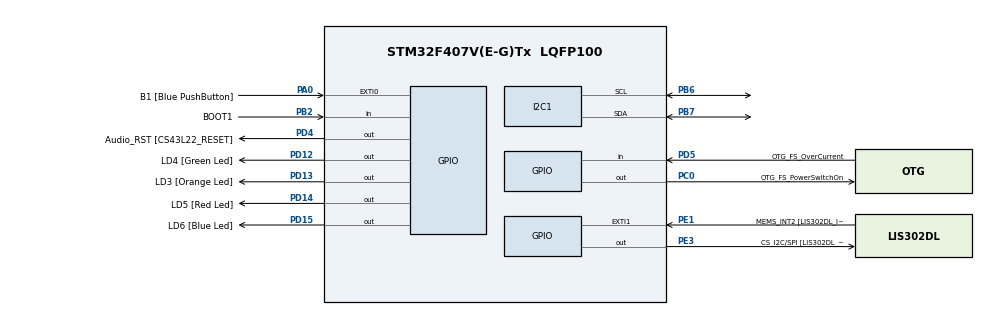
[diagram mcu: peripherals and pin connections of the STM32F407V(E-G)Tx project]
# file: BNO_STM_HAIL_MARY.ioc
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Mcu.Family=STM32F4
Mcu.Name=STM32F407V(E-G)Tx
Mcu.Package=LQFP100
NVIC.PriorityGroup=NVIC_PRIORITYGROUP_0
PA0-WKUP.GPIO_Label=B1 [Blue PushButton]
PA0-WKUP.Signal=GPXTI0
PA10.GPIO_Label=OTG_FS_ID
PA10.GPIO_Mode=GPIO_MODE_AF_PP
PA10.GPIO_PuPd=GPIO_NOPULL
PA10.GPIO_Speed=GPIO_SPEED_FREQ_LOW
PA10.Signal=USB_OTG_FS_ID
PA11.GPIO_Label=OTG_FS_DM
PA11.GPIO_Mode=GPIO_MODE_AF_PP
PA11.GPIO_PuPd=GPIO_NOPULL
PA11.GPIO_Speed=GPIO_SPEED_FREQ_LOW
PA11.Signal=USB_OTG_FS_DM
PA12.GPIO_Label=OTG_FS_DP
PA12.GPIO_Mode=GPIO_MODE_AF_PP
PA12.GPIO_PuPd=GPIO_NOPULL
PA12.GPIO_Speed=GPIO_SPEED_FREQ_LOW
PA12.Signal=USB_OTG_FS_DP
PA13.GPIO_Label=SWDIO
PA13.Signal=SYS_JTMS-SWDIO
PA14.GPIO_Label=SWCLK
PA14.Signal=SYS_JTCK-SWCLK
PA4.GPIO_Label=I2S3_WS [CS43L22_LRCK]
PA4.GPIO_Mode=GPIO_MODE_AF_PP
PA4.GPIO_PuPd=GPIO_NOPULL
PA4.GPIO_Speed=GPIO_SPEED_FREQ_LOW
PA4.Signal=I2S3_WS
PA5.GPIO_Label=SPI1_SCK [LIS302DL_SCL/SPC]
PA5.GPIO_Mode=GPIO_MODE_AF_PP
PA5.GPIO_PuPd=GPIO_NOPULL
PA5.GPIO_Speed=GPIO_SPEED_FREQ_LOW
PA5.Signal=SPI1_SCK
PA6.GPIO_Label=SPI1_MISO [LIS302DL_SDO]
PA6.GPIO_Mode=GPIO_MODE_AF_PP
PA6.GPIO_PuPd=GPIO_NOPULL
PA6.GPIO_Speed=GPIO_SPEED_FREQ_LOW
PA6.Signal=SPI1_MISO
PA7.GPIO_Label=SPI1_MOSI [LIS302DL_SDA/SDI/SDO]
PA7.GPIO_Mode=GPIO_MODE_AF_PP
PA7.GPIO_PuPd=GPIO_NOPULL
PA7.GPIO_Speed=GPIO_SPEED_FREQ_LOW
PA7.Signal=SPI1_MOSI
PA9.GPIO_Label=VBUS_FS
PA9.GPIO_Mode=GPIO_MODE_INPUT
PA9.GPIO_PuPd=GPIO_NOPULL
PA9.Signal=USB_OTG_FS_VBUS
PB10.GPIO_Label=CLK_IN [MP45DT02_CLK]
PB10.GPIO_Mode=GPIO_MODE_AF_PP
PB10.GPIO_PuPd=GPIO_NOPULL
PB10.GPIO_Speed=GPIO_SPEED_FREQ_LOW
PB10.Signal=I2S2_CK
PB2.GPIO_Label=BOOT1
PB2.GPIO_Mode=GPIO_MODE_INPUT
PB2.GPIO_PuPd=GPIO_NOPULL
PB2.Signal=GPIO_Input
PB3.GPIO_Label=SWO
PB3.Signal=SYS_JTDO-SWO
PB6.Mode=I2C
PB6.Signal=I2C1_SCL
PB7.Mode=I2C
PB7.Signal=I2C1_SDA
PC0.GPIO_Label=OTG_FS_PowerSwitchOn
PC0.GPIO_PuPd=GPIO_NOPULL
PC0.GPIO_Speed=GPIO_SPEED_FREQ_LOW
PC0.PinState=GPIO_PIN_SET
PC0.Signal=GPIO_Output
PC10.GPIO_Label=I2S3_SCK [CS43L22_SCLK]
PC10.GPIO_Mode=GPIO_MODE_AF_PP
PC10.GPIO_PuPd=GPIO_NOPULL
PC10.GPIO_Speed=GPIO_SPEED_FREQ_LOW
PC10.Signal=I2S3_CK
PC12.GPIO_Label=I2S3_SD [CS43L22_SDIN]
PC12.GPIO_Mode=GPIO_MODE_AF_PP
PC12.GPIO_PuPd=GPIO_NOPULL
PC12.GPIO_Speed=GPIO_SPEED_FREQ_LOW
PC12.Signal=I2S3_SD
PC14-OSC32_IN.GPIO_Label=PC14-OSC32_IN
PC14-OSC32_IN.Signal=RCC_OSC32_IN
PC15-OSC32_OUT.GPIO_Label=PC15-OSC32_OUT
PC15-OSC32_OUT.Signal=RCC_OSC32_OUT
PC3.GPIO_Label=PDM_OUT [MP45DT02_DOUT]
PC3.GPIO_Mode=GPIO_MODE_AF_PP
PC3.GPIO_PuPd=GPIO_NOPULL
PC3.GPIO_Speed=GPIO_SPEED_FREQ_LOW
PC3.Signal=I2S2_SD
PC7.GPIO_Label=I2S3_MCK [CS43L22_MCLK]
PC7.GPIO_Mode=GPIO_MODE_AF_PP
PC7.GPIO_PuPd=GPIO_NOPULL
PC7.GPIO_Speed=GPIO_SPEED_FREQ_LOW
PC7.Signal=I2S3_MCK
PD12.GPIO_Label=LD4 [Green Led]
PD12.GPIO_PuPd=GPIO_NOPULL
PD12.GPIO_Speed=GPIO_SPEED_FREQ_LOW
PD12.Signal=GPIO_Output
PD13.GPIO_Label=LD3 [Orange Led]
PD13.GPIO_PuPd=GPIO_NOPULL
PD13.GPIO_Speed=GPIO_SPEED_FREQ_LOW
PD13.Signal=GPIO_Output
PD14.GPIO_Label=LD5 [Red Led]
PD14.GPIO_PuPd=GPIO_NOPULL
PD14.GPIO_Speed=GPIO_SPEED_FREQ_LOW
PD14.Signal=GPIO_Output
PD15.GPIO_Label=LD6 [Blue Led]
PD15.GPIO_PuPd=GPIO_NOPULL
PD15.GPIO_Speed=GPIO_SPEED_FREQ_LOW
PD15.Signal=GPIO_Output
PD4.GPIO_Label=Audio_RST [CS43L22_RESET]
PD4.GPIO_PuPd=GPIO_NOPULL
PD4.GPIO_Speed=GPIO_SPEED_FREQ_LOW
PD4.Signal=GPIO_Output
PD5.GPIO_Label=OTG_FS_OverCurrent
PD5.GPIO_Mode=GPIO_MODE_INPUT
PD5.GPIO_PuPd=GPIO_NOPULL
PD5.Signal=GPIO_Input
PE1.GPIO_Label=MEMS_INT2 [LIS302DL_INT2]
PE1.GPIO_ModeDefaultEXTI=GPIO_MODE_EVT_RISING
PE1.GPIO_PuPd=GPIO_NOPULL
PE1.Signal=GPXTI1
PE3.GPIO_Label=CS_I2C/SPI [LIS302DL_CS_I2C/SPI]
PE3.GPIO_PuPd=GPIO_NOPULL
PE3.GPIO_Speed=GPIO_SPEED_FREQ_LOW
PE3.Signal=GPIO_Output
PH0-OSC_IN.GPIO_Label=PH0-OSC_IN
PH0-OSC_IN.Signal=RCC_OSC_IN
PH1-OSC_OUT.GPIO_Label=PH1-OSC_OUT
PH1-OSC_OUT.Signal=RCC_OSC_OUT
ProjectManager.HeapSize=0x200
ProjectManager.StackSize=0x400
ProjectManager.TargetToolchain=STM32CubeIDE
RCC.48MHZClocksFreq_Value=24000000
RCC.AHBCLKDivider=RCC_SYSCLK_DIV2
RCC.AHBFreq_Value=42000000
RCC.APB1CLKDivider=RCC_HCLK_DIV4
RCC.APB1Freq_Value=10500000
RCC.APB1TimFreq_Value=21000000
RCC.APB2CLKDivider=RCC_HCLK_DIV2
RCC.APB2Freq_Value=21000000
RCC.APB2TimFreq_Value=42000000
RCC.CortexFreq_Value=42000000
RCC.HCLKFreq_Value=42000000
RCC.HSE_VALUE=8000000
RCC.HSI_VALUE=16000000
RCC.LSE_VALUE=32768
RCC.PLLM=8
RCC.PLLN=84
RCC.PLLQ=7
RCC.SYSCLKFreq_VALUE=84000000
RCC.SYSCLKSource=RCC_SYSCLKSOURCE_PLLCLK
RCC.VCOOutputFreq_Value=168000000
board=STM32F407G-DISC1

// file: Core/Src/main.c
#include <stdbool.h>
#include <stdio.h>

//#include "../../../bno055.h"
//#include "../../../bno_config.h"
 #include "bno055.h"
 #include "bno_config.h"
#include "main.h"
//#include "retarget.h"
#include "stm32f4xx_hal.h"
#include "stm32f4xx_hal_gpio.h"
#include "stm32f4xx_hal_gpio_ex.h"

I2C_HandleTypeDef hi2c1;
I2C_HandleTypeDef hi2c2;
bno055_t bno;
error_bno err;

void SystemClock_Config(void);
static void MX_GPIO_Init(void);
static void MX_I2C1_Init(void);

// static void MX_I2C2_Init(void);

int main(void) {
    /* Reset of all peripherals, Initializes the Flash interface and the
     * Systick. */
    HAL_Init();

    /* Configure the system clock */
    SystemClock_Config();
    /* Initialize all configured peripherals */
    MX_GPIO_Init();
//    uart_init();
    MX_I2C1_Init();
    // MX_I2C2_Init();

    bno = (bno055_t){
        .i2c = &hi2c1, .addr = BNO_ADDR, .mode = BNO_MODE_IMU, ._temp_unit = 0,
        // .ptr = &bno,
    };
    HAL_Delay(1000);

    if ((err = bno055_init(&bno)) == BNO_OK) {
        printf("[+] BNO055 init success\r\n");

        HAL_Delay(100);
    } else {
        printf("[!] BNO055 init failed\r\n");
        printf("%s\n", bno055_err_str(err));
        Error_Handler();
    }
    HAL_Delay(100);
    err = bno055_set_unit(&bno, BNO_TEMP_UNIT_C, BNO_GYR_UNIT_DPS,
                          BNO_ACC_UNITSEL_M_S2, BNO_EUL_UNIT_DEG);
    if (err != BNO_OK) {
        printf("[BNO] Failed to set units. Err: %d\r\n", err);
    } else {
        printf("[BNO] Unit selection success\r\n");
    }

    HAL_Delay(1000);
    s8 temperature = 0;
    // f32 acc_x = 0.0f, acc_y = 0.0f, acc_z = 0.0f;
    bno055_vec3_t acc = {0, 0, 0};
    bno055_vec3_t lia = {0, 0, 0};
    bno055_vec3_t gyr = {0, 0, 0};
    bno055_vec3_t mag = {0, 0, 0};
    bno055_vec3_t grv = {0, 0, 0};
    bno055_euler_t eul = {0, 0, 0};
    bno055_vec4_t qua = {0, 0, 0};
    while (1) {
        // bno055_temperature(&bno, &temperature);
        bno.temperature(&bno, &temperature);
        bno.acc(&bno, &acc);
        bno.linear_acc(&bno, &lia);
        bno.gyro(&bno, &gyr);
        bno.mag(&bno, &mag);
        bno.gravity(&bno, &grv);
        bno.euler(&bno, &eul);
        bno.quaternion(&bno, &qua);
        printf("[+] Temperature: %2d°C\r\n", temperature);
//        printf("[+] ACC - x: %+2.2f | y: %+2.2f | z: %+2.2f\r\n", acc.x, acc.y,
//               acc.z);
//        printf("[+] LIA - x: %+2.2f | y: %+2.2f | z: %+2.2f\r\n", lia.x, lia.y,
//               lia.z);
//        printf("[+] GYR - x: %+2.2f | y: %+2.2f | z: %+2.2f\r\n", gyr.x, gyr.y,
//               gyr.z);
//        printf("[+] MAG - x: %+2.2f | y: %+2.2f | z: %+2.2f\r\n", mag.x, mag.y,
//               mag.z);
//        printf("[+] GRV - x: %+2.2f | y: %+2.2f | z: %+2.2f\r\n", grv.x, grv.y,
//               grv.z);
//        printf("[+] Roll: %+2.2f | Pitch: %+2.2f | Yaw: %+2.2f\r\n", eul.roll,
//               eul.pitch, eul.yaw);
//        printf("[+] QUA - w: %+2.2f | x: %+2.2f | y: %+2.2f | z: %+2.2f\r\n",
//               qua.w, qua.x, qua.y, qua.z);
//        HAL_GPIO_TogglePin(STATUS_LED_PORT, STATUS_LED);
        HAL_Delay(100);
    }
}

static void MX_I2C1_Init(void) {
    __HAL_RCC_I2C1_CLK_ENABLE();
    hi2c1.Instance = I2C1;
    hi2c1.Init.ClockSpeed = 100000;
    hi2c1.Init.DutyCycle = I2C_DUTYCYCLE_2;
    hi2c1.Init.OwnAddress1 = 0;
    hi2c1.Init.AddressingMode = I2C_ADDRESSINGMODE_7BIT;
    hi2c1.Init.DualAddressMode = I2C_DUALADDRESS_DISABLE;
    hi2c1.Init.OwnAddress2 = 0;
    hi2c1.Init.GeneralCallMode = I2C_GENERALCALL_DISABLE;
    hi2c1.Init.NoStretchMode = I2C_NOSTRETCH_DISABLE;
    if (HAL_I2C_Init(&hi2c1) != HAL_OK) {
        Error_Handler();
    }
}

// static void MX_I2C2_Init(void) {
//     __HAL_RCC_I2C2_CLK_ENABLE();
//     hi2c2.Instance = I2C2;
//     hi2c2.Init.ClockSpeed = 100000;
//     hi2c2.Init.DutyCycle = I2C_DUTYCYCLE_2;
//     hi2c2.Init.OwnAddress1 = 0;
//     hi2c2.Init.AddressingMode = I2C_ADDRESSINGMODE_7BIT;
//     hi2c2.Init.DualAddressMode = I2C_DUALADDRESS_DISABLE;
//     hi2c2.Init.OwnAddress2 = 0;
//     hi2c2.Init.GeneralCallMode = I2C_GENERALCALL_DISABLE;
//     hi2c2.Init.NoStretchMode = I2C_NOSTRETCH_DISABLE;
//     if (HAL_I2C_Init(&hi2c2) != HAL_OK) {
//         Error_Handler();
//     }
// }

static void MX_GPIO_Init(void) {
    /* GPIO Ports Clock Enable */
    __HAL_RCC_GPIOC_CLK_ENABLE();
    __HAL_RCC_GPIOH_CLK_ENABLE();
    __HAL_RCC_GPIOB_CLK_ENABLE();
    __HAL_RCC_GPIOA_CLK_ENABLE();

    GPIO_InitTypeDef gpio = {0};
    gpio.Speed = GPIO_SPEED_FREQ_LOW;
    gpio.Mode = GPIO_MODE_OUTPUT_PP;
    gpio.Pin = ERROR_LED;
    gpio.Pull = GPIO_NOPULL;
    HAL_GPIO_Init(ERROR_LED_PORT, &gpio);

    gpio.Speed = GPIO_SPEED_FREQ_LOW;
    gpio.Mode = GPIO_MODE_OUTPUT_PP;
    gpio.Pin = STATUS_LED;
    gpio.Pull = GPIO_NOPULL;
    HAL_GPIO_Init(STATUS_LED_PORT, &gpio);

    gpio.Speed = GPIO_SPEED_FREQ_MEDIUM;
    gpio.Mode = GPIO_MODE_AF_OD;
    gpio.Alternate = GPIO_AF4_I2C1;
    gpio.Pin = I2C1_SCL | I2C1_SDA;
    gpio.Pull = GPIO_NOPULL;
    HAL_GPIO_Init(I2C1_PORT, &gpio);

    // gpio.Speed = GPIO_SPEED_FREQ_MEDIUM;
    // gpio.Mode = GPIO_MODE_AF_OD;
    // gpio.Alternate = GPIO_AF4_I2C2;
    // gpio.Pin =  I2C2_SCL;
    // gpio.Pull = GPIO_NOPULL;
    // HAL_GPIO_Init(I2C2_PORT, &gpio);

    // gpio.Speed = GPIO_SPEED_FREQ_MEDIUM;
    // gpio.Mode = GPIO_MODE_AF_OD;
    // gpio.Alternate = GPIO_AF9_I2C2;
    // gpio.Pin =  I2C2_SDA;
    // gpio.Pull = GPIO_NOPULL;
    // HAL_GPIO_Init(I2C2_PORT, &gpio);
}

void SystemClock_Config(void) {
    /* SysTick_IRQn interrupt configuration */
    RCC_OscInitTypeDef RCC_OscInitStruct = {0};
    RCC_ClkInitTypeDef RCC_ClkInitStruct = {0};

    /** Configure the main internal regulator output voltage
     */
    __HAL_RCC_PWR_CLK_ENABLE();
    __HAL_PWR_VOLTAGESCALING_CONFIG(PWR_REGULATOR_VOLTAGE_SCALE1);
    /** Initializes the RCC Oscillators according to the specified parameters
     * in the RCC_OscInitTypeDef structure.
     */
    RCC_OscInitStruct.OscillatorType = RCC_OSCILLATORTYPE_HSI;
    RCC_OscInitStruct.HSIState = RCC_HSI_ON;
    RCC_OscInitStruct.HSICalibrationValue = RCC_HSICALIBRATION_DEFAULT;
    RCC_OscInitStruct.PLL.PLLState = RCC_PLL_ON;
    RCC_OscInitStruct.PLL.PLLSource = RCC_PLLSOURCE_HSI;
    RCC_OscInitStruct.PLL.PLLM = 8;
    RCC_OscInitStruct.PLL.PLLN = 192;
    RCC_OscInitStruct.PLL.PLLP = RCC_PLLP_DIV4;
    RCC_OscInitStruct.PLL.PLLQ = 8;
    if (HAL_RCC_OscConfig(&RCC_OscInitStruct) != HAL_OK) {
        Error_Handler();
    }
    /** Initializes the CPU, AHB and APB buses clocks
     */
    RCC_ClkInitStruct.ClockType = RCC_CLOCKTYPE_HCLK | RCC_CLOCKTYPE_SYSCLK |
                                  RCC_CLOCKTYPE_PCLK1 | RCC_CLOCKTYPE_PCLK2;
    RCC_ClkInitStruct.SYSCLKSource = RCC_SYSCLKSOURCE_PLLCLK;
    RCC_ClkInitStruct.AHBCLKDivider = RCC_SYSCLK_DIV1;
    RCC_ClkInitStruct.APB1CLKDivider = RCC_HCLK_DIV4;
    RCC_ClkInitStruct.APB2CLKDivider = RCC_HCLK_DIV2;

    if (HAL_RCC_ClockConfig(&RCC_ClkInitStruct, FLASH_LATENCY_3) != HAL_OK) {
        Error_Handler();
    }
    HAL_NVIC_SetPriority(SysTick_IRQn, 0, 0);
}

void Error_Handler(void) {
    /* USER CODE BEGIN Error_Handler_Debug */
    /* User can add his own implementation to report the HAL error return state
     */
    //__disable_irq();
    while (1) {
        HAL_Delay(200);
    }
    /* USER CODE END Error_Handler_Debug */
}

#ifdef USE_FULL_ASSERT
/**
 * @brief  Reports the name of the source file and the source line number
 *         where the assert_param error has occurred.
 * @param  file: pointer to the source file name
 * @param  line: assert_param error line source number
 * @retval None
 */
void assert_failed(uint8_t* file, uint32_t line) {
    /* USER CODE BEGIN 6 */
    /* User can add his own implementation to report the file name and line
       number, ex: printf("Wrong parameters value: file %s on line %d\r\n",
       file, line) */
    /* USER CODE END 6 */
}
#endif /* USE_FULL_ASSERT */
